VERSION 5.8 ;
BUSBITCHARS "[]" ;
DIVIDERCHAR "/" ;
UNITS
    DATABASE MICRONS 1000 ;
END UNITS

VIA ino_exec_arith_via1_2_1000_440_1_2_410_410
  VIARULE via1Array ;
  CUTSIZE 0.19 0.19 ;
  LAYERS Metal1 Via1 Metal2 ;
  CUTSPACING 0.22 0.22 ;
  ENCLOSURE 0.05 0.125 0.005 0.05 ;
  ROWCOL 1 2 ;
END ino_exec_arith_via1_2_1000_440_1_2_410_410

VIA ino_exec_arith_via2_3_1000_440_1_2_410_410
  VIARULE via2Array ;
  CUTSIZE 0.19 0.19 ;
  LAYERS Metal2 Via2 Metal3 ;
  CUTSPACING 0.22 0.22 ;
  ENCLOSURE 0.005 0.05 0.05 0.005 ;
  ROWCOL 1 2 ;
END ino_exec_arith_via2_3_1000_440_1_2_410_410

VIA ino_exec_arith_via3_4_1000_440_1_2_410_410
  VIARULE via3Array ;
  CUTSIZE 0.19 0.19 ;
  LAYERS Metal3 Via3 Metal4 ;
  CUTSPACING 0.22 0.22 ;
  ENCLOSURE 0.05 0.005 0.2 0.05 ;
  ROWCOL 1 2 ;
END ino_exec_arith_via3_4_1000_440_1_2_410_410

VIA ino_exec_arith_via4_5_1000_2000_1_1_840_840
  VIARULE viaTop1Array ;
  CUTSIZE 0.42 0.42 ;
  LAYERS Metal4 TopVia1 TopMetal1 ;
  CUTSPACING 0.42 0.42 ;
  ENCLOSURE 0.29 0.1 0.42 0.79 ;
END ino_exec_arith_via4_5_1000_2000_1_1_840_840

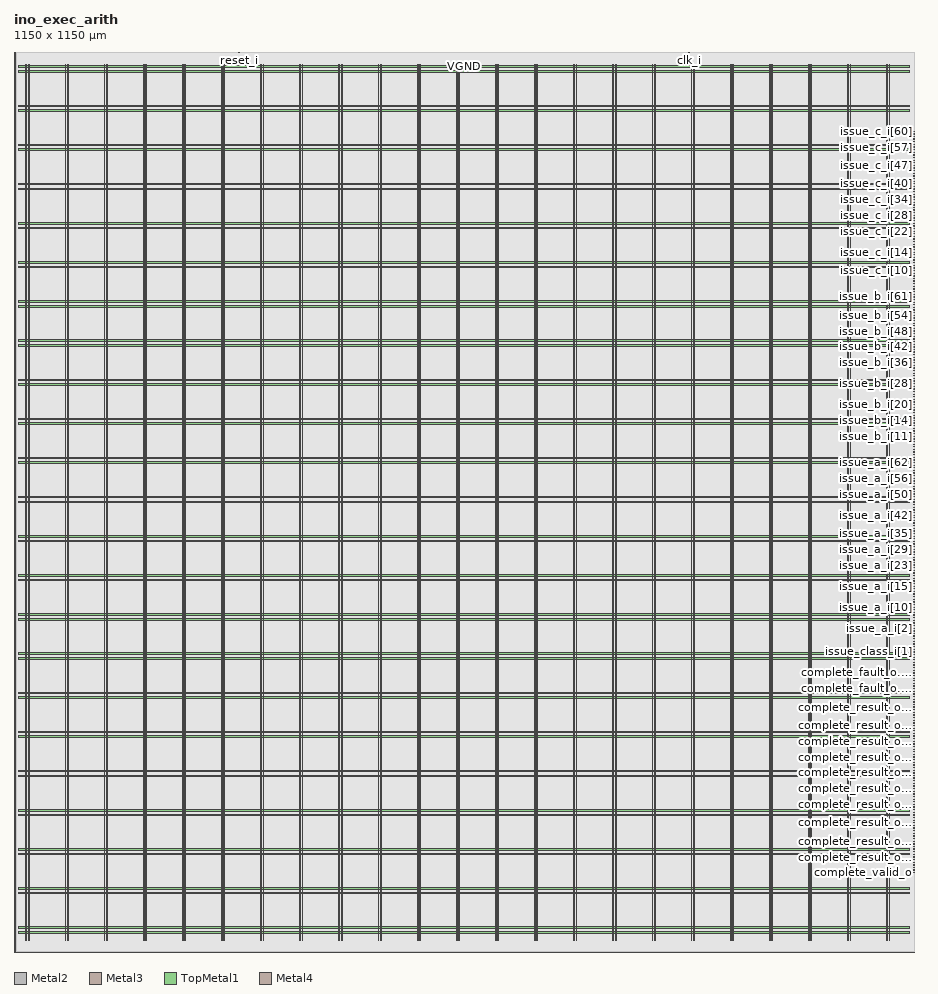
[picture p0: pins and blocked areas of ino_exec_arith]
MACRO ino_exec_arith
  FOREIGN ino_exec_arith 0 0 ;
  CLASS BLOCK ;
  SIZE 1150 BY 1150 ;
  PIN clk_i
    DIRECTION INPUT ;
    USE SIGNAL ;
    PORT
      LAYER Metal2 ;
        RECT  862.36 1149.6 862.76 1150 ;
    END
  END clk_i
  PIN complete_fault_o.code[0]
    DIRECTION OUTPUT ;
    USE SIGNAL ;
    PORT
      LAYER Metal3 ;
        RECT  1149.6 336.22 1150 336.62 ;
    END
  END complete_fault_o.code[0]
  PIN complete_fault_o.code[1]
    DIRECTION OUTPUT ;
    USE SIGNAL ;
    PORT
      LAYER Metal3 ;
        RECT  1149.6 339.58 1150 339.98 ;
    END
  END complete_fault_o.code[1]
  PIN complete_fault_o.code[2]
    DIRECTION OUTPUT ;
    USE SIGNAL ;
    PORT
      LAYER Metal3 ;
        RECT  1149.6 342.94 1150 343.34 ;
    END
  END complete_fault_o.code[2]
  PIN complete_fault_o.code[3]
    DIRECTION OUTPUT ;
    USE SIGNAL ;
    PORT
      LAYER Metal3 ;
        RECT  1149.6 346.3 1150 346.7 ;
    END
  END complete_fault_o.code[3]
  PIN complete_fault_o.code[4]
    DIRECTION OUTPUT ;
    USE SIGNAL ;
    PORT
      LAYER Metal3 ;
        RECT  1149.6 349.66 1150 350.06 ;
    END
  END complete_fault_o.code[4]
  PIN complete_fault_o.code[5]
    DIRECTION OUTPUT ;
    USE SIGNAL ;
    PORT
      LAYER Metal3 ;
        RECT  1149.6 353.02 1150 353.42 ;
    END
  END complete_fault_o.code[5]
  PIN complete_fault_o.code[6]
    DIRECTION OUTPUT ;
    USE SIGNAL ;
    PORT
      LAYER Metal3 ;
        RECT  1149.6 356.38 1150 356.78 ;
    END
  END complete_fault_o.code[6]
  PIN complete_fault_o.code[7]
    DIRECTION OUTPUT ;
    USE SIGNAL ;
    PORT
      LAYER Metal3 ;
        RECT  1149.6 359.74 1150 360.14 ;
    END
  END complete_fault_o.code[7]
  PIN complete_fault_o.valid
    DIRECTION OUTPUT ;
    USE SIGNAL ;
    PORT
      LAYER Metal3 ;
        RECT  1149.6 332.86 1150 333.26 ;
    END
  END complete_fault_o.valid
  PIN complete_result_o[0]
    DIRECTION OUTPUT ;
    USE SIGNAL ;
    PORT
      LAYER Metal3 ;
        RECT  1149.6 117.82 1150 118.22 ;
    END
  END complete_result_o[0]
  PIN complete_result_o[10]
    DIRECTION OUTPUT ;
    USE SIGNAL ;
    PORT
      LAYER Metal3 ;
        RECT  1149.6 151.42 1150 151.82 ;
    END
  END complete_result_o[10]
  PIN complete_result_o[11]
    DIRECTION OUTPUT ;
    USE SIGNAL ;
    PORT
      LAYER Metal3 ;
        RECT  1149.6 154.78 1150 155.18 ;
    END
  END complete_result_o[11]
  PIN complete_result_o[12]
    DIRECTION OUTPUT ;
    USE SIGNAL ;
    PORT
      LAYER Metal3 ;
        RECT  1149.6 158.14 1150 158.54 ;
    END
  END complete_result_o[12]
  PIN complete_result_o[13]
    DIRECTION OUTPUT ;
    USE SIGNAL ;
    PORT
      LAYER Metal3 ;
        RECT  1149.6 161.5 1150 161.9 ;
    END
  END complete_result_o[13]
  PIN complete_result_o[14]
    DIRECTION OUTPUT ;
    USE SIGNAL ;
    PORT
      LAYER Metal3 ;
        RECT  1149.6 164.86 1150 165.26 ;
    END
  END complete_result_o[14]
  PIN complete_result_o[15]
    DIRECTION OUTPUT ;
    USE SIGNAL ;
    PORT
      LAYER Metal3 ;
        RECT  1149.6 168.22 1150 168.62 ;
    END
  END complete_result_o[15]
  PIN complete_result_o[16]
    DIRECTION OUTPUT ;
    USE SIGNAL ;
    PORT
      LAYER Metal3 ;
        RECT  1149.6 171.58 1150 171.98 ;
    END
  END complete_result_o[16]
  PIN complete_result_o[17]
    DIRECTION OUTPUT ;
    USE SIGNAL ;
    PORT
      LAYER Metal3 ;
        RECT  1149.6 174.94 1150 175.34 ;
    END
  END complete_result_o[17]
  PIN complete_result_o[18]
    DIRECTION OUTPUT ;
    USE SIGNAL ;
    PORT
      LAYER Metal3 ;
        RECT  1149.6 178.3 1150 178.7 ;
    END
  END complete_result_o[18]
  PIN complete_result_o[19]
    DIRECTION OUTPUT ;
    USE SIGNAL ;
    PORT
      LAYER Metal3 ;
        RECT  1149.6 181.66 1150 182.06 ;
    END
  END complete_result_o[19]
  PIN complete_result_o[1]
    DIRECTION OUTPUT ;
    USE SIGNAL ;
    PORT
      LAYER Metal3 ;
        RECT  1149.6 121.18 1150 121.58 ;
    END
  END complete_result_o[1]
  PIN complete_result_o[20]
    DIRECTION OUTPUT ;
    USE SIGNAL ;
    PORT
      LAYER Metal3 ;
        RECT  1149.6 185.02 1150 185.42 ;
    END
  END complete_result_o[20]
  PIN complete_result_o[21]
    DIRECTION OUTPUT ;
    USE SIGNAL ;
    PORT
      LAYER Metal3 ;
        RECT  1149.6 188.38 1150 188.78 ;
    END
  END complete_result_o[21]
  PIN complete_result_o[22]
    DIRECTION OUTPUT ;
    USE SIGNAL ;
    PORT
      LAYER Metal3 ;
        RECT  1149.6 191.74 1150 192.14 ;
    END
  END complete_result_o[22]
  PIN complete_result_o[23]
    DIRECTION OUTPUT ;
    USE SIGNAL ;
    PORT
      LAYER Metal3 ;
        RECT  1149.6 195.1 1150 195.5 ;
    END
  END complete_result_o[23]
  PIN complete_result_o[24]
    DIRECTION OUTPUT ;
    USE SIGNAL ;
    PORT
      LAYER Metal3 ;
        RECT  1149.6 198.46 1150 198.86 ;
    END
  END complete_result_o[24]
  PIN complete_result_o[25]
    DIRECTION OUTPUT ;
    USE SIGNAL ;
    PORT
      LAYER Metal3 ;
        RECT  1149.6 201.82 1150 202.22 ;
    END
  END complete_result_o[25]
  PIN complete_result_o[26]
    DIRECTION OUTPUT ;
    USE SIGNAL ;
    PORT
      LAYER Metal3 ;
        RECT  1149.6 205.18 1150 205.58 ;
    END
  END complete_result_o[26]
  PIN complete_result_o[27]
    DIRECTION OUTPUT ;
    USE SIGNAL ;
    PORT
      LAYER Metal3 ;
        RECT  1149.6 208.54 1150 208.94 ;
    END
  END complete_result_o[27]
  PIN complete_result_o[28]
    DIRECTION OUTPUT ;
    USE SIGNAL ;
    PORT
      LAYER Metal3 ;
        RECT  1149.6 211.9 1150 212.3 ;
    END
  END complete_result_o[28]
  PIN complete_result_o[29]
    DIRECTION OUTPUT ;
    USE SIGNAL ;
    PORT
      LAYER Metal3 ;
        RECT  1149.6 215.26 1150 215.66 ;
    END
  END complete_result_o[29]
  PIN complete_result_o[2]
    DIRECTION OUTPUT ;
    USE SIGNAL ;
    PORT
      LAYER Metal3 ;
        RECT  1149.6 124.54 1150 124.94 ;
    END
  END complete_result_o[2]
  PIN complete_result_o[30]
    DIRECTION OUTPUT ;
    USE SIGNAL ;
    PORT
      LAYER Metal3 ;
        RECT  1149.6 218.62 1150 219.02 ;
    END
  END complete_result_o[30]
  PIN complete_result_o[31]
    DIRECTION OUTPUT ;
    USE SIGNAL ;
    PORT
      LAYER Metal3 ;
        RECT  1149.6 221.98 1150 222.38 ;
    END
  END complete_result_o[31]
  PIN complete_result_o[32]
    DIRECTION OUTPUT ;
    USE SIGNAL ;
    PORT
      LAYER Metal3 ;
        RECT  1149.6 225.34 1150 225.74 ;
    END
  END complete_result_o[32]
  PIN complete_result_o[33]
    DIRECTION OUTPUT ;
    USE SIGNAL ;
    PORT
      LAYER Metal3 ;
        RECT  1149.6 228.7 1150 229.1 ;
    END
  END complete_result_o[33]
  PIN complete_result_o[34]
    DIRECTION OUTPUT ;
    USE SIGNAL ;
    PORT
      LAYER Metal3 ;
        RECT  1149.6 232.06 1150 232.46 ;
    END
  END complete_result_o[34]
  PIN complete_result_o[35]
    DIRECTION OUTPUT ;
    USE SIGNAL ;
    PORT
      LAYER Metal3 ;
        RECT  1149.6 235.42 1150 235.82 ;
    END
  END complete_result_o[35]
  PIN complete_result_o[36]
    DIRECTION OUTPUT ;
    USE SIGNAL ;
    PORT
      LAYER Metal3 ;
        RECT  1149.6 238.78 1150 239.18 ;
    END
  END complete_result_o[36]
  PIN complete_result_o[37]
    DIRECTION OUTPUT ;
    USE SIGNAL ;
    PORT
      LAYER Metal3 ;
        RECT  1149.6 242.14 1150 242.54 ;
    END
  END complete_result_o[37]
  PIN complete_result_o[38]
    DIRECTION OUTPUT ;
    USE SIGNAL ;
    PORT
      LAYER Metal3 ;
        RECT  1149.6 245.5 1150 245.9 ;
    END
  END complete_result_o[38]
  PIN complete_result_o[39]
    DIRECTION OUTPUT ;
    USE SIGNAL ;
    PORT
      LAYER Metal3 ;
        RECT  1149.6 248.86 1150 249.26 ;
    END
  END complete_result_o[39]
  PIN complete_result_o[3]
    DIRECTION OUTPUT ;
    USE SIGNAL ;
    PORT
      LAYER Metal3 ;
        RECT  1149.6 127.9 1150 128.3 ;
    END
  END complete_result_o[3]
  PIN complete_result_o[40]
    DIRECTION OUTPUT ;
    USE SIGNAL ;
    PORT
      LAYER Metal3 ;
        RECT  1149.6 252.22 1150 252.62 ;
    END
  END complete_result_o[40]
  PIN complete_result_o[41]
    DIRECTION OUTPUT ;
    USE SIGNAL ;
    PORT
      LAYER Metal3 ;
        RECT  1149.6 255.58 1150 255.98 ;
    END
  END complete_result_o[41]
  PIN complete_result_o[42]
    DIRECTION OUTPUT ;
    USE SIGNAL ;
    PORT
      LAYER Metal3 ;
        RECT  1149.6 258.94 1150 259.34 ;
    END
  END complete_result_o[42]
  PIN complete_result_o[43]
    DIRECTION OUTPUT ;
    USE SIGNAL ;
    PORT
      LAYER Metal3 ;
        RECT  1149.6 262.3 1150 262.7 ;
    END
  END complete_result_o[43]
  PIN complete_result_o[44]
    DIRECTION OUTPUT ;
    USE SIGNAL ;
    PORT
      LAYER Metal3 ;
        RECT  1149.6 265.66 1150 266.06 ;
    END
  END complete_result_o[44]
  PIN complete_result_o[45]
    DIRECTION OUTPUT ;
    USE SIGNAL ;
    PORT
      LAYER Metal3 ;
        RECT  1149.6 269.02 1150 269.42 ;
    END
  END complete_result_o[45]
  PIN complete_result_o[46]
    DIRECTION OUTPUT ;
    USE SIGNAL ;
    PORT
      LAYER Metal3 ;
        RECT  1149.6 272.38 1150 272.78 ;
    END
  END complete_result_o[46]
  PIN complete_result_o[47]
    DIRECTION OUTPUT ;
    USE SIGNAL ;
    PORT
      LAYER Metal3 ;
        RECT  1149.6 275.74 1150 276.14 ;
    END
  END complete_result_o[47]
  PIN complete_result_o[48]
    DIRECTION OUTPUT ;
    USE SIGNAL ;
    PORT
      LAYER Metal3 ;
        RECT  1149.6 279.1 1150 279.5 ;
    END
  END complete_result_o[48]
  PIN complete_result_o[49]
    DIRECTION OUTPUT ;
    USE SIGNAL ;
    PORT
      LAYER Metal3 ;
        RECT  1149.6 282.46 1150 282.86 ;
    END
  END complete_result_o[49]
  PIN complete_result_o[4]
    DIRECTION OUTPUT ;
    USE SIGNAL ;
    PORT
      LAYER Metal3 ;
        RECT  1149.6 131.26 1150 131.66 ;
    END
  END complete_result_o[4]
  PIN complete_result_o[50]
    DIRECTION OUTPUT ;
    USE SIGNAL ;
    PORT
      LAYER Metal3 ;
        RECT  1149.6 285.82 1150 286.22 ;
    END
  END complete_result_o[50]
  PIN complete_result_o[51]
    DIRECTION OUTPUT ;
    USE SIGNAL ;
    PORT
      LAYER Metal3 ;
        RECT  1149.6 289.18 1150 289.58 ;
    END
  END complete_result_o[51]
  PIN complete_result_o[52]
    DIRECTION OUTPUT ;
    USE SIGNAL ;
    PORT
      LAYER Metal3 ;
        RECT  1149.6 292.54 1150 292.94 ;
    END
  END complete_result_o[52]
  PIN complete_result_o[53]
    DIRECTION OUTPUT ;
    USE SIGNAL ;
    PORT
      LAYER Metal3 ;
        RECT  1149.6 295.9 1150 296.3 ;
    END
  END complete_result_o[53]
  PIN complete_result_o[54]
    DIRECTION OUTPUT ;
    USE SIGNAL ;
    PORT
      LAYER Metal3 ;
        RECT  1149.6 299.26 1150 299.66 ;
    END
  END complete_result_o[54]
  PIN complete_result_o[55]
    DIRECTION OUTPUT ;
    USE SIGNAL ;
    PORT
      LAYER Metal3 ;
        RECT  1149.6 302.62 1150 303.02 ;
    END
  END complete_result_o[55]
  PIN complete_result_o[56]
    DIRECTION OUTPUT ;
    USE SIGNAL ;
    PORT
      LAYER Metal3 ;
        RECT  1149.6 305.98 1150 306.38 ;
    END
  END complete_result_o[56]
  PIN complete_result_o[57]
    DIRECTION OUTPUT ;
    USE SIGNAL ;
    PORT
      LAYER Metal3 ;
        RECT  1149.6 309.34 1150 309.74 ;
    END
  END complete_result_o[57]
  PIN complete_result_o[58]
    DIRECTION OUTPUT ;
    USE SIGNAL ;
    PORT
      LAYER Metal3 ;
        RECT  1149.6 312.7 1150 313.1 ;
    END
  END complete_result_o[58]
  PIN complete_result_o[59]
    DIRECTION OUTPUT ;
    USE SIGNAL ;
    PORT
      LAYER Metal3 ;
        RECT  1149.6 316.06 1150 316.46 ;
    END
  END complete_result_o[59]
  PIN complete_result_o[5]
    DIRECTION OUTPUT ;
    USE SIGNAL ;
    PORT
      LAYER Metal3 ;
        RECT  1149.6 134.62 1150 135.02 ;
    END
  END complete_result_o[5]
  PIN complete_result_o[60]
    DIRECTION OUTPUT ;
    USE SIGNAL ;
    PORT
      LAYER Metal3 ;
        RECT  1149.6 319.42 1150 319.82 ;
    END
  END complete_result_o[60]
  PIN complete_result_o[61]
    DIRECTION OUTPUT ;
    USE SIGNAL ;
    PORT
      LAYER Metal3 ;
        RECT  1149.6 322.78 1150 323.18 ;
    END
  END complete_result_o[61]
  PIN complete_result_o[62]
    DIRECTION OUTPUT ;
    USE SIGNAL ;
    PORT
      LAYER Metal3 ;
        RECT  1149.6 326.14 1150 326.54 ;
    END
  END complete_result_o[62]
  PIN complete_result_o[63]
    DIRECTION OUTPUT ;
    USE SIGNAL ;
    PORT
      LAYER Metal3 ;
        RECT  1149.6 329.5 1150 329.9 ;
    END
  END complete_result_o[63]
  PIN complete_result_o[6]
    DIRECTION OUTPUT ;
    USE SIGNAL ;
    PORT
      LAYER Metal3 ;
        RECT  1149.6 137.98 1150 138.38 ;
    END
  END complete_result_o[6]
  PIN complete_result_o[7]
    DIRECTION OUTPUT ;
    USE SIGNAL ;
    PORT
      LAYER Metal3 ;
        RECT  1149.6 141.34 1150 141.74 ;
    END
  END complete_result_o[7]
  PIN complete_result_o[8]
    DIRECTION OUTPUT ;
    USE SIGNAL ;
    PORT
      LAYER Metal3 ;
        RECT  1149.6 144.7 1150 145.1 ;
    END
  END complete_result_o[8]
  PIN complete_result_o[9]
    DIRECTION OUTPUT ;
    USE SIGNAL ;
    PORT
      LAYER Metal3 ;
        RECT  1149.6 148.06 1150 148.46 ;
    END
  END complete_result_o[9]
  PIN complete_result_valid_o
    DIRECTION OUTPUT ;
    USE SIGNAL ;
    PORT
      LAYER Metal3 ;
        RECT  1149.6 114.46 1150 114.86 ;
    END
  END complete_result_valid_o
  PIN complete_valid_o
    DIRECTION OUTPUT ;
    USE SIGNAL ;
    PORT
      LAYER Metal3 ;
        RECT  1149.6 111.1 1150 111.5 ;
    END
  END complete_valid_o
  PIN issue_a_i[0]
    DIRECTION INPUT ;
    USE SIGNAL ;
    PORT
      LAYER Metal3 ;
        RECT  1149.6 406.78 1150 407.18 ;
    END
  END issue_a_i[0]
  PIN issue_a_i[10]
    DIRECTION INPUT ;
    USE SIGNAL ;
    PORT
      LAYER Metal3 ;
        RECT  1149.6 440.38 1150 440.78 ;
    END
  END issue_a_i[10]
  PIN issue_a_i[11]
    DIRECTION INPUT ;
    USE SIGNAL ;
    PORT
      LAYER Metal3 ;
        RECT  1149.6 443.74 1150 444.14 ;
    END
  END issue_a_i[11]
  PIN issue_a_i[12]
    DIRECTION INPUT ;
    USE SIGNAL ;
    PORT
      LAYER Metal3 ;
        RECT  1149.6 447.1 1150 447.5 ;
    END
  END issue_a_i[12]
  PIN issue_a_i[13]
    DIRECTION INPUT ;
    USE SIGNAL ;
    PORT
      LAYER Metal3 ;
        RECT  1149.6 450.46 1150 450.86 ;
    END
  END issue_a_i[13]
  PIN issue_a_i[14]
    DIRECTION INPUT ;
    USE SIGNAL ;
    PORT
      LAYER Metal3 ;
        RECT  1149.6 453.82 1150 454.22 ;
    END
  END issue_a_i[14]
  PIN issue_a_i[15]
    DIRECTION INPUT ;
    USE SIGNAL ;
    PORT
      LAYER Metal3 ;
        RECT  1149.6 457.18 1150 457.58 ;
    END
  END issue_a_i[15]
  PIN issue_a_i[16]
    DIRECTION INPUT ;
    USE SIGNAL ;
    PORT
      LAYER Metal3 ;
        RECT  1149.6 460.54 1150 460.94 ;
    END
  END issue_a_i[16]
  PIN issue_a_i[17]
    DIRECTION INPUT ;
    USE SIGNAL ;
    PORT
      LAYER Metal3 ;
        RECT  1149.6 463.9 1150 464.3 ;
    END
  END issue_a_i[17]
  PIN issue_a_i[18]
    DIRECTION INPUT ;
    USE SIGNAL ;
    PORT
      LAYER Metal3 ;
        RECT  1149.6 467.26 1150 467.66 ;
    END
  END issue_a_i[18]
  PIN issue_a_i[19]
    DIRECTION INPUT ;
    USE SIGNAL ;
    PORT
      LAYER Metal3 ;
        RECT  1149.6 470.62 1150 471.02 ;
    END
  END issue_a_i[19]
  PIN issue_a_i[1]
    DIRECTION INPUT ;
    USE SIGNAL ;
    PORT
      LAYER Metal3 ;
        RECT  1149.6 410.14 1150 410.54 ;
    END
  END issue_a_i[1]
  PIN issue_a_i[20]
    DIRECTION INPUT ;
    USE SIGNAL ;
    PORT
      LAYER Metal3 ;
        RECT  1149.6 473.98 1150 474.38 ;
    END
  END issue_a_i[20]
  PIN issue_a_i[21]
    DIRECTION INPUT ;
    USE SIGNAL ;
    PORT
      LAYER Metal3 ;
        RECT  1149.6 477.34 1150 477.74 ;
    END
  END issue_a_i[21]
  PIN issue_a_i[22]
    DIRECTION INPUT ;
    USE SIGNAL ;
    PORT
      LAYER Metal3 ;
        RECT  1149.6 480.7 1150 481.1 ;
    END
  END issue_a_i[22]
  PIN issue_a_i[23]
    DIRECTION INPUT ;
    USE SIGNAL ;
    PORT
      LAYER Metal3 ;
        RECT  1149.6 484.06 1150 484.46 ;
    END
  END issue_a_i[23]
  PIN issue_a_i[24]
    DIRECTION INPUT ;
    USE SIGNAL ;
    PORT
      LAYER Metal3 ;
        RECT  1149.6 487.42 1150 487.82 ;
    END
  END issue_a_i[24]
  PIN issue_a_i[25]
    DIRECTION INPUT ;
    USE SIGNAL ;
    PORT
      LAYER Metal3 ;
        RECT  1149.6 490.78 1150 491.18 ;
    END
  END issue_a_i[25]
  PIN issue_a_i[26]
    DIRECTION INPUT ;
    USE SIGNAL ;
    PORT
      LAYER Metal3 ;
        RECT  1149.6 494.14 1150 494.54 ;
    END
  END issue_a_i[26]
  PIN issue_a_i[27]
    DIRECTION INPUT ;
    USE SIGNAL ;
    PORT
      LAYER Metal3 ;
        RECT  1149.6 497.5 1150 497.9 ;
    END
  END issue_a_i[27]
  PIN issue_a_i[28]
    DIRECTION INPUT ;
    USE SIGNAL ;
    PORT
      LAYER Metal3 ;
        RECT  1149.6 500.86 1150 501.26 ;
    END
  END issue_a_i[28]
  PIN issue_a_i[29]
    DIRECTION INPUT ;
    USE SIGNAL ;
    PORT
      LAYER Metal3 ;
        RECT  1149.6 504.22 1150 504.62 ;
    END
  END issue_a_i[29]
  PIN issue_a_i[2]
    DIRECTION INPUT ;
    USE SIGNAL ;
    PORT
      LAYER Metal3 ;
        RECT  1149.6 413.5 1150 413.9 ;
    END
  END issue_a_i[2]
  PIN issue_a_i[30]
    DIRECTION INPUT ;
    USE SIGNAL ;
    PORT
      LAYER Metal3 ;
        RECT  1149.6 507.58 1150 507.98 ;
    END
  END issue_a_i[30]
  PIN issue_a_i[31]
    DIRECTION INPUT ;
    USE SIGNAL ;
    PORT
      LAYER Metal3 ;
        RECT  1149.6 510.94 1150 511.34 ;
    END
  END issue_a_i[31]
  PIN issue_a_i[32]
    DIRECTION INPUT ;
    USE SIGNAL ;
    PORT
      LAYER Metal3 ;
        RECT  1149.6 514.3 1150 514.7 ;
    END
  END issue_a_i[32]
  PIN issue_a_i[33]
    DIRECTION INPUT ;
    USE SIGNAL ;
    PORT
      LAYER Metal3 ;
        RECT  1149.6 517.66 1150 518.06 ;
    END
  END issue_a_i[33]
  PIN issue_a_i[34]
    DIRECTION INPUT ;
    USE SIGNAL ;
    PORT
      LAYER Metal3 ;
        RECT  1149.6 521.02 1150 521.42 ;
    END
  END issue_a_i[34]
  PIN issue_a_i[35]
    DIRECTION INPUT ;
    USE SIGNAL ;
    PORT
      LAYER Metal3 ;
        RECT  1149.6 524.38 1150 524.78 ;
    END
  END issue_a_i[35]
  PIN issue_a_i[36]
    DIRECTION INPUT ;
    USE SIGNAL ;
    PORT
      LAYER Metal3 ;
        RECT  1149.6 527.74 1150 528.14 ;
    END
  END issue_a_i[36]
  PIN issue_a_i[37]
    DIRECTION INPUT ;
    USE SIGNAL ;
    PORT
      LAYER Metal3 ;
        RECT  1149.6 531.1 1150 531.5 ;
    END
  END issue_a_i[37]
  PIN issue_a_i[38]
    DIRECTION INPUT ;
    USE SIGNAL ;
    PORT
      LAYER Metal3 ;
        RECT  1149.6 534.46 1150 534.86 ;
    END
  END issue_a_i[38]
  PIN issue_a_i[39]
    DIRECTION INPUT ;
    USE SIGNAL ;
    PORT
      LAYER Metal3 ;
        RECT  1149.6 537.82 1150 538.22 ;
    END
  END issue_a_i[39]
  PIN issue_a_i[3]
    DIRECTION INPUT ;
    USE SIGNAL ;
    PORT
      LAYER Metal3 ;
        RECT  1149.6 416.86 1150 417.26 ;
    END
  END issue_a_i[3]
  PIN issue_a_i[40]
    DIRECTION INPUT ;
    USE SIGNAL ;
    PORT
      LAYER Metal3 ;
        RECT  1149.6 541.18 1150 541.58 ;
    END
  END issue_a_i[40]
  PIN issue_a_i[41]
    DIRECTION INPUT ;
    USE SIGNAL ;
    PORT
      LAYER Metal3 ;
        RECT  1149.6 544.54 1150 544.94 ;
    END
  END issue_a_i[41]
  PIN issue_a_i[42]
    DIRECTION INPUT ;
    USE SIGNAL ;
    PORT
      LAYER Metal3 ;
        RECT  1149.6 547.9 1150 548.3 ;
    END
  END issue_a_i[42]
  PIN issue_a_i[43]
    DIRECTION INPUT ;
    USE SIGNAL ;
    PORT
      LAYER Metal3 ;
        RECT  1149.6 551.26 1150 551.66 ;
    END
  END issue_a_i[43]
  PIN issue_a_i[44]
    DIRECTION INPUT ;
    USE SIGNAL ;
    PORT
      LAYER Metal3 ;
        RECT  1149.6 554.62 1150 555.02 ;
    END
  END issue_a_i[44]
  PIN issue_a_i[45]
    DIRECTION INPUT ;
    USE SIGNAL ;
    PORT
      LAYER Metal3 ;
        RECT  1149.6 557.98 1150 558.38 ;
    END
  END issue_a_i[45]
  PIN issue_a_i[46]
    DIRECTION INPUT ;
    USE SIGNAL ;
    PORT
      LAYER Metal3 ;
        RECT  1149.6 561.34 1150 561.74 ;
    END
  END issue_a_i[46]
  PIN issue_a_i[47]
    DIRECTION INPUT ;
    USE SIGNAL ;
    PORT
      LAYER Metal3 ;
        RECT  1149.6 564.7 1150 565.1 ;
    END
  END issue_a_i[47]
  PIN issue_a_i[48]
    DIRECTION INPUT ;
    USE SIGNAL ;
    PORT
      LAYER Metal3 ;
        RECT  1149.6 568.06 1150 568.46 ;
    END
  END issue_a_i[48]
  PIN issue_a_i[49]
    DIRECTION INPUT ;
    USE SIGNAL ;
    PORT
      LAYER Metal3 ;
        RECT  1149.6 571.42 1150 571.82 ;
    END
  END issue_a_i[49]
  PIN issue_a_i[4]
    DIRECTION INPUT ;
    USE SIGNAL ;
    PORT
      LAYER Metal3 ;
        RECT  1149.6 420.22 1150 420.62 ;
    END
  END issue_a_i[4]
  PIN issue_a_i[50]
    DIRECTION INPUT ;
    USE SIGNAL ;
    PORT
      LAYER Metal3 ;
        RECT  1149.6 574.78 1150 575.18 ;
    END
  END issue_a_i[50]
  PIN issue_a_i[51]
    DIRECTION INPUT ;
    USE SIGNAL ;
    PORT
      LAYER Metal3 ;
        RECT  1149.6 578.14 1150 578.54 ;
    END
  END issue_a_i[51]
  PIN issue_a_i[52]
    DIRECTION INPUT ;
    USE SIGNAL ;
    PORT
      LAYER Metal3 ;
        RECT  1149.6 581.5 1150 581.9 ;
    END
  END issue_a_i[52]
  PIN issue_a_i[53]
    DIRECTION INPUT ;
    USE SIGNAL ;
    PORT
      LAYER Metal3 ;
        RECT  1149.6 584.86 1150 585.26 ;
    END
  END issue_a_i[53]
  PIN issue_a_i[54]
    DIRECTION INPUT ;
    USE SIGNAL ;
    PORT
      LAYER Metal3 ;
        RECT  1149.6 588.22 1150 588.62 ;
    END
  END issue_a_i[54]
  PIN issue_a_i[55]
    DIRECTION INPUT ;
    USE SIGNAL ;
    PORT
      LAYER Metal3 ;
        RECT  1149.6 591.58 1150 591.98 ;
    END
  END issue_a_i[55]
  PIN issue_a_i[56]
    DIRECTION INPUT ;
    USE SIGNAL ;
    PORT
      LAYER Metal3 ;
        RECT  1149.6 594.94 1150 595.34 ;
    END
  END issue_a_i[56]
  PIN issue_a_i[57]
    DIRECTION INPUT ;
    USE SIGNAL ;
    PORT
      LAYER Metal3 ;
        RECT  1149.6 598.3 1150 598.7 ;
    END
  END issue_a_i[57]
  PIN issue_a_i[58]
    DIRECTION INPUT ;
    USE SIGNAL ;
    PORT
      LAYER Metal3 ;
        RECT  1149.6 601.66 1150 602.06 ;
    END
  END issue_a_i[58]
  PIN issue_a_i[59]
    DIRECTION INPUT ;
    USE SIGNAL ;
    PORT
      LAYER Metal3 ;
        RECT  1149.6 605.02 1150 605.42 ;
    END
  END issue_a_i[59]
  PIN issue_a_i[5]
    DIRECTION INPUT ;
    USE SIGNAL ;
    PORT
      LAYER Metal3 ;
        RECT  1149.6 423.58 1150 423.98 ;
    END
  END issue_a_i[5]
  PIN issue_a_i[60]
    DIRECTION INPUT ;
    USE SIGNAL ;
    PORT
      LAYER Metal3 ;
        RECT  1149.6 608.38 1150 608.78 ;
    END
  END issue_a_i[60]
  PIN issue_a_i[61]
    DIRECTION INPUT ;
    USE SIGNAL ;
    PORT
      LAYER Metal3 ;
        RECT  1149.6 611.74 1150 612.14 ;
    END
  END issue_a_i[61]
  PIN issue_a_i[62]
    DIRECTION INPUT ;
    USE SIGNAL ;
    PORT
      LAYER Metal3 ;
        RECT  1149.6 615.1 1150 615.5 ;
    END
  END issue_a_i[62]
  PIN issue_a_i[63]
    DIRECTION INPUT ;
    USE SIGNAL ;
    PORT
      LAYER Metal3 ;
        RECT  1149.6 618.46 1150 618.86 ;
    END
  END issue_a_i[63]
  PIN issue_a_i[6]
    DIRECTION INPUT ;
    USE SIGNAL ;
    PORT
      LAYER Metal3 ;
        RECT  1149.6 426.94 1150 427.34 ;
    END
  END issue_a_i[6]
  PIN issue_a_i[7]
    DIRECTION INPUT ;
    USE SIGNAL ;
    PORT
      LAYER Metal3 ;
        RECT  1149.6 430.3 1150 430.7 ;
    END
  END issue_a_i[7]
  PIN issue_a_i[8]
    DIRECTION INPUT ;
    USE SIGNAL ;
    PORT
      LAYER Metal3 ;
        RECT  1149.6 433.66 1150 434.06 ;
    END
  END issue_a_i[8]
  PIN issue_a_i[9]
    DIRECTION INPUT ;
    USE SIGNAL ;
    PORT
      LAYER Metal3 ;
        RECT  1149.6 437.02 1150 437.42 ;
    END
  END issue_a_i[9]
  PIN issue_b_i[0]
    DIRECTION INPUT ;
    USE SIGNAL ;
    PORT
      LAYER Metal3 ;
        RECT  1149.6 621.82 1150 622.22 ;
    END
  END issue_b_i[0]
  PIN issue_b_i[10]
    DIRECTION INPUT ;
    USE SIGNAL ;
    PORT
      LAYER Metal3 ;
        RECT  1149.6 655.42 1150 655.82 ;
    END
  END issue_b_i[10]
  PIN issue_b_i[11]
    DIRECTION INPUT ;
    USE SIGNAL ;
    PORT
      LAYER Metal3 ;
        RECT  1149.6 658.78 1150 659.18 ;
    END
  END issue_b_i[11]
  PIN issue_b_i[12]
    DIRECTION INPUT ;
    USE SIGNAL ;
    PORT
      LAYER Metal3 ;
        RECT  1149.6 662.14 1150 662.54 ;
    END
  END issue_b_i[12]
  PIN issue_b_i[13]
    DIRECTION INPUT ;
    USE SIGNAL ;
    PORT
      LAYER Metal3 ;
        RECT  1149.6 665.5 1150 665.9 ;
    END
  END issue_b_i[13]
  PIN issue_b_i[14]
    DIRECTION INPUT ;
    USE SIGNAL ;
    PORT
      LAYER Metal3 ;
        RECT  1149.6 668.86 1150 669.26 ;
    END
  END issue_b_i[14]
  PIN issue_b_i[15]
    DIRECTION INPUT ;
    USE SIGNAL ;
    PORT
      LAYER Metal3 ;
        RECT  1149.6 672.22 1150 672.62 ;
    END
  END issue_b_i[15]
  PIN issue_b_i[16]
    DIRECTION INPUT ;
    USE SIGNAL ;
    PORT
      LAYER Metal3 ;
        RECT  1149.6 675.58 1150 675.98 ;
    END
  END issue_b_i[16]
  PIN issue_b_i[17]
    DIRECTION INPUT ;
    USE SIGNAL ;
    PORT
      LAYER Metal3 ;
        RECT  1149.6 678.94 1150 679.34 ;
    END
  END issue_b_i[17]
  PIN issue_b_i[18]
    DIRECTION INPUT ;
    USE SIGNAL ;
    PORT
      LAYER Metal3 ;
        RECT  1149.6 682.3 1150 682.7 ;
    END
  END issue_b_i[18]
  PIN issue_b_i[19]
    DIRECTION INPUT ;
    USE SIGNAL ;
    PORT
      LAYER Metal3 ;
        RECT  1149.6 685.66 1150 686.06 ;
    END
  END issue_b_i[19]
  PIN issue_b_i[1]
    DIRECTION INPUT ;
    USE SIGNAL ;
    PORT
      LAYER Metal3 ;
        RECT  1149.6 625.18 1150 625.58 ;
    END
  END issue_b_i[1]
  PIN issue_b_i[20]
    DIRECTION INPUT ;
    USE SIGNAL ;
    PORT
      LAYER Metal3 ;
        RECT  1149.6 689.02 1150 689.42 ;
    END
  END issue_b_i[20]
  PIN issue_b_i[21]
    DIRECTION INPUT ;
    USE SIGNAL ;
    PORT
      LAYER Metal3 ;
        RECT  1149.6 692.38 1150 692.78 ;
    END
  END issue_b_i[21]
  PIN issue_b_i[22]
    DIRECTION INPUT ;
    USE SIGNAL ;
    PORT
      LAYER Metal3 ;
        RECT  1149.6 695.74 1150 696.14 ;
    END
  END issue_b_i[22]
  PIN issue_b_i[23]
    DIRECTION INPUT ;
    USE SIGNAL ;
    PORT
      LAYER Metal3 ;
        RECT  1149.6 699.1 1150 699.5 ;
    END
  END issue_b_i[23]
  PIN issue_b_i[24]
    DIRECTION INPUT ;
    USE SIGNAL ;
    PORT
      LAYER Metal3 ;
        RECT  1149.6 702.46 1150 702.86 ;
    END
  END issue_b_i[24]
  PIN issue_b_i[25]
    DIRECTION INPUT ;
    USE SIGNAL ;
    PORT
      LAYER Metal3 ;
        RECT  1149.6 705.82 1150 706.22 ;
    END
  END issue_b_i[25]
  PIN issue_b_i[26]
    DIRECTION INPUT ;
    USE SIGNAL ;
    PORT
      LAYER Metal3 ;
        RECT  1149.6 709.18 1150 709.58 ;
    END
  END issue_b_i[26]
  PIN issue_b_i[27]
    DIRECTION INPUT ;
    USE SIGNAL ;
    PORT
      LAYER Metal3 ;
        RECT  1149.6 712.54 1150 712.94 ;
    END
  END issue_b_i[27]
  PIN issue_b_i[28]
    DIRECTION INPUT ;
    USE SIGNAL ;
    PORT
      LAYER Metal3 ;
        RECT  1149.6 715.9 1150 716.3 ;
    END
  END issue_b_i[28]
  PIN issue_b_i[29]
    DIRECTION INPUT ;
    USE SIGNAL ;
    PORT
      LAYER Metal3 ;
        RECT  1149.6 719.26 1150 719.66 ;
    END
  END issue_b_i[29]
  PIN issue_b_i[2]
    DIRECTION INPUT ;
    USE SIGNAL ;
    PORT
      LAYER Metal3 ;
        RECT  1149.6 628.54 1150 628.94 ;
    END
  END issue_b_i[2]
  PIN issue_b_i[30]
    DIRECTION INPUT ;
    USE SIGNAL ;
    PORT
      LAYER Metal3 ;
        RECT  1149.6 722.62 1150 723.02 ;
    END
  END issue_b_i[30]
  PIN issue_b_i[31]
    DIRECTION INPUT ;
    USE SIGNAL ;
    PORT
      LAYER Metal3 ;
        RECT  1149.6 725.98 1150 726.38 ;
    END
  END issue_b_i[31]
  PIN issue_b_i[32]
    DIRECTION INPUT ;
    USE SIGNAL ;
    PORT
      LAYER Metal3 ;
        RECT  1149.6 729.34 1150 729.74 ;
    END
  END issue_b_i[32]
  PIN issue_b_i[33]
    DIRECTION INPUT ;
    USE SIGNAL ;
    PORT
      LAYER Metal3 ;
        RECT  1149.6 732.7 1150 733.1 ;
    END
  END issue_b_i[33]
  PIN issue_b_i[34]
    DIRECTION INPUT ;
    USE SIGNAL ;
    PORT
      LAYER Metal3 ;
        RECT  1149.6 736.06 1150 736.46 ;
    END
  END issue_b_i[34]
  PIN issue_b_i[35]
    DIRECTION INPUT ;
    USE SIGNAL ;
    PORT
      LAYER Metal3 ;
        RECT  1149.6 739.42 1150 739.82 ;
    END
  END issue_b_i[35]
  PIN issue_b_i[36]
    DIRECTION INPUT ;
    USE SIGNAL ;
    PORT
      LAYER Metal3 ;
        RECT  1149.6 742.78 1150 743.18 ;
    END
  END issue_b_i[36]
  PIN issue_b_i[37]
    DIRECTION INPUT ;
    USE SIGNAL ;
    PORT
      LAYER Metal3 ;
        RECT  1149.6 746.14 1150 746.54 ;
    END
  END issue_b_i[37]
  PIN issue_b_i[38]
    DIRECTION INPUT ;
    USE SIGNAL ;
    PORT
      LAYER Metal3 ;
        RECT  1149.6 749.5 1150 749.9 ;
    END
  END issue_b_i[38]
  PIN issue_b_i[39]
    DIRECTION INPUT ;
    USE SIGNAL ;
    PORT
      LAYER Metal3 ;
        RECT  1149.6 752.86 1150 753.26 ;
    END
  END issue_b_i[39]
  PIN issue_b_i[3]
    DIRECTION INPUT ;
    USE SIGNAL ;
    PORT
      LAYER Metal3 ;
        RECT  1149.6 631.9 1150 632.3 ;
    END
  END issue_b_i[3]
  PIN issue_b_i[40]
    DIRECTION INPUT ;
    USE SIGNAL ;
    PORT
      LAYER Metal3 ;
        RECT  1149.6 756.22 1150 756.62 ;
    END
  END issue_b_i[40]
  PIN issue_b_i[41]
    DIRECTION INPUT ;
    USE SIGNAL ;
    PORT
      LAYER Metal3 ;
        RECT  1149.6 759.58 1150 759.98 ;
    END
  END issue_b_i[41]
  PIN issue_b_i[42]
    DIRECTION INPUT ;
    USE SIGNAL ;
    PORT
      LAYER Metal3 ;
        RECT  1149.6 762.94 1150 763.34 ;
    END
  END issue_b_i[42]
  PIN issue_b_i[43]
    DIRECTION INPUT ;
    USE SIGNAL ;
    PORT
      LAYER Metal3 ;
        RECT  1149.6 766.3 1150 766.7 ;
    END
  END issue_b_i[43]
  PIN issue_b_i[44]
    DIRECTION INPUT ;
    USE SIGNAL ;
    PORT
      LAYER Metal3 ;
        RECT  1149.6 769.66 1150 770.06 ;
    END
  END issue_b_i[44]
  PIN issue_b_i[45]
    DIRECTION INPUT ;
    USE SIGNAL ;
    PORT
      LAYER Metal3 ;
        RECT  1149.6 773.02 1150 773.42 ;
    END
  END issue_b_i[45]
  PIN issue_b_i[46]
    DIRECTION INPUT ;
    USE SIGNAL ;
    PORT
      LAYER Metal3 ;
        RECT  1149.6 776.38 1150 776.78 ;
    END
  END issue_b_i[46]
  PIN issue_b_i[47]
    DIRECTION INPUT ;
    USE SIGNAL ;
    PORT
      LAYER Metal3 ;
        RECT  1149.6 779.74 1150 780.14 ;
    END
  END issue_b_i[47]
  PIN issue_b_i[48]
    DIRECTION INPUT ;
    USE SIGNAL ;
    PORT
      LAYER Metal3 ;
        RECT  1149.6 783.1 1150 783.5 ;
    END
  END issue_b_i[48]
  PIN issue_b_i[49]
    DIRECTION INPUT ;
    USE SIGNAL ;
    PORT
      LAYER Metal3 ;
        RECT  1149.6 786.46 1150 786.86 ;
    END
  END issue_b_i[49]
  PIN issue_b_i[4]
    DIRECTION INPUT ;
    USE SIGNAL ;
    PORT
      LAYER Metal3 ;
        RECT  1149.6 635.26 1150 635.66 ;
    END
  END issue_b_i[4]
  PIN issue_b_i[50]
    DIRECTION INPUT ;
    USE SIGNAL ;
    PORT
      LAYER Metal3 ;
        RECT  1149.6 789.82 1150 790.22 ;
    END
  END issue_b_i[50]
  PIN issue_b_i[51]
    DIRECTION INPUT ;
    USE SIGNAL ;
    PORT
      LAYER Metal3 ;
        RECT  1149.6 793.18 1150 793.58 ;
    END
  END issue_b_i[51]
  PIN issue_b_i[52]
    DIRECTION INPUT ;
    USE SIGNAL ;
    PORT
      LAYER Metal3 ;
        RECT  1149.6 796.54 1150 796.94 ;
    END
  END issue_b_i[52]
  PIN issue_b_i[53]
    DIRECTION INPUT ;
    USE SIGNAL ;
    PORT
      LAYER Metal3 ;
        RECT  1149.6 799.9 1150 800.3 ;
    END
  END issue_b_i[53]
  PIN issue_b_i[54]
    DIRECTION INPUT ;
    USE SIGNAL ;
    PORT
      LAYER Metal3 ;
        RECT  1149.6 803.26 1150 803.66 ;
    END
  END issue_b_i[54]
  PIN issue_b_i[55]
    DIRECTION INPUT ;
    USE SIGNAL ;
    PORT
      LAYER Metal3 ;
        RECT  1149.6 806.62 1150 807.02 ;
    END
  END issue_b_i[55]
  PIN issue_b_i[56]
    DIRECTION INPUT ;
    USE SIGNAL ;
    PORT
      LAYER Metal3 ;
        RECT  1149.6 809.98 1150 810.38 ;
    END
  END issue_b_i[56]
  PIN issue_b_i[57]
    DIRECTION INPUT ;
    USE SIGNAL ;
    PORT
      LAYER Metal3 ;
        RECT  1149.6 813.34 1150 813.74 ;
    END
  END issue_b_i[57]
  PIN issue_b_i[58]
    DIRECTION INPUT ;
    USE SIGNAL ;
    PORT
      LAYER Metal3 ;
        RECT  1149.6 816.7 1150 817.1 ;
    END
  END issue_b_i[58]
  PIN issue_b_i[59]
    DIRECTION INPUT ;
    USE SIGNAL ;
    PORT
      LAYER Metal3 ;
        RECT  1149.6 820.06 1150 820.46 ;
    END
  END issue_b_i[59]
  PIN issue_b_i[5]
    DIRECTION INPUT ;
    USE SIGNAL ;
    PORT
      LAYER Metal3 ;
        RECT  1149.6 638.62 1150 639.02 ;
    END
  END issue_b_i[5]
  PIN issue_b_i[60]
    DIRECTION INPUT ;
    USE SIGNAL ;
    PORT
      LAYER Metal3 ;
        RECT  1149.6 823.42 1150 823.82 ;
    END
  END issue_b_i[60]
  PIN issue_b_i[61]
    DIRECTION INPUT ;
    USE SIGNAL ;
    PORT
      LAYER Metal3 ;
        RECT  1149.6 826.78 1150 827.18 ;
    END
  END issue_b_i[61]
  PIN issue_b_i[62]
    DIRECTION INPUT ;
    USE SIGNAL ;
    PORT
      LAYER Metal3 ;
        RECT  1149.6 830.14 1150 830.54 ;
    END
  END issue_b_i[62]
  PIN issue_b_i[63]
    DIRECTION INPUT ;
    USE SIGNAL ;
    PORT
      LAYER Metal3 ;
        RECT  1149.6 833.5 1150 833.9 ;
    END
  END issue_b_i[63]
  PIN issue_b_i[6]
    DIRECTION INPUT ;
    USE SIGNAL ;
    PORT
      LAYER Metal3 ;
        RECT  1149.6 641.98 1150 642.38 ;
    END
  END issue_b_i[6]
  PIN issue_b_i[7]
    DIRECTION INPUT ;
    USE SIGNAL ;
    PORT
      LAYER Metal3 ;
        RECT  1149.6 645.34 1150 645.74 ;
    END
  END issue_b_i[7]
  PIN issue_b_i[8]
    DIRECTION INPUT ;
    USE SIGNAL ;
    PORT
      LAYER Metal3 ;
        RECT  1149.6 648.7 1150 649.1 ;
    END
  END issue_b_i[8]
  PIN issue_b_i[9]
    DIRECTION INPUT ;
    USE SIGNAL ;
    PORT
      LAYER Metal3 ;
        RECT  1149.6 652.06 1150 652.46 ;
    END
  END issue_b_i[9]
  PIN issue_c_i[0]
    DIRECTION INPUT ;
    USE SIGNAL ;
    PORT
      LAYER Metal3 ;
        RECT  1149.6 836.86 1150 837.26 ;
    END
  END issue_c_i[0]
  PIN issue_c_i[10]
    DIRECTION INPUT ;
    USE SIGNAL ;
    PORT
      LAYER Metal3 ;
        RECT  1149.6 870.46 1150 870.86 ;
    END
  END issue_c_i[10]
  PIN issue_c_i[11]
    DIRECTION INPUT ;
    USE SIGNAL ;
    PORT
      LAYER Metal3 ;
        RECT  1149.6 873.82 1150 874.22 ;
    END
  END issue_c_i[11]
  PIN issue_c_i[12]
    DIRECTION INPUT ;
    USE SIGNAL ;
    PORT
      LAYER Metal3 ;
        RECT  1149.6 877.18 1150 877.58 ;
    END
  END issue_c_i[12]
  PIN issue_c_i[13]
    DIRECTION INPUT ;
    USE SIGNAL ;
    PORT
      LAYER Metal3 ;
        RECT  1149.6 880.54 1150 880.94 ;
    END
  END issue_c_i[13]
  PIN issue_c_i[14]
    DIRECTION INPUT ;
    USE SIGNAL ;
    PORT
      LAYER Metal3 ;
        RECT  1149.6 883.9 1150 884.3 ;
    END
  END issue_c_i[14]
  PIN issue_c_i[15]
    DIRECTION INPUT ;
    USE SIGNAL ;
    PORT
      LAYER Metal3 ;
        RECT  1149.6 887.26 1150 887.66 ;
    END
  END issue_c_i[15]
  PIN issue_c_i[16]
    DIRECTION INPUT ;
    USE SIGNAL ;
    PORT
      LAYER Metal3 ;
        RECT  1149.6 890.62 1150 891.02 ;
    END
  END issue_c_i[16]
  PIN issue_c_i[17]
    DIRECTION INPUT ;
    USE SIGNAL ;
    PORT
      LAYER Metal3 ;
        RECT  1149.6 893.98 1150 894.38 ;
    END
  END issue_c_i[17]
  PIN issue_c_i[18]
    DIRECTION INPUT ;
    USE SIGNAL ;
    PORT
      LAYER Metal3 ;
        RECT  1149.6 897.34 1150 897.74 ;
    END
  END issue_c_i[18]
  PIN issue_c_i[19]
    DIRECTION INPUT ;
    USE SIGNAL ;
    PORT
      LAYER Metal3 ;
        RECT  1149.6 900.7 1150 901.1 ;
    END
  END issue_c_i[19]
  PIN issue_c_i[1]
    DIRECTION INPUT ;
    USE SIGNAL ;
    PORT
      LAYER Metal3 ;
        RECT  1149.6 840.22 1150 840.62 ;
    END
  END issue_c_i[1]
  PIN issue_c_i[20]
    DIRECTION INPUT ;
    USE SIGNAL ;
    PORT
      LAYER Metal3 ;
        RECT  1149.6 904.06 1150 904.46 ;
    END
  END issue_c_i[20]
  PIN issue_c_i[21]
    DIRECTION INPUT ;
    USE SIGNAL ;
    PORT
      LAYER Metal3 ;
        RECT  1149.6 907.42 1150 907.82 ;
    END
  END issue_c_i[21]
  PIN issue_c_i[22]
    DIRECTION INPUT ;
    USE SIGNAL ;
    PORT
      LAYER Metal3 ;
        RECT  1149.6 910.78 1150 911.18 ;
    END
  END issue_c_i[22]
  PIN issue_c_i[23]
    DIRECTION INPUT ;
    USE SIGNAL ;
    PORT
      LAYER Metal3 ;
        RECT  1149.6 914.14 1150 914.54 ;
    END
  END issue_c_i[23]
  PIN issue_c_i[24]
    DIRECTION INPUT ;
    USE SIGNAL ;
    PORT
      LAYER Metal3 ;
        RECT  1149.6 917.5 1150 917.9 ;
    END
  END issue_c_i[24]
  PIN issue_c_i[25]
    DIRECTION INPUT ;
    USE SIGNAL ;
    PORT
      LAYER Metal3 ;
        RECT  1149.6 920.86 1150 921.26 ;
    END
  END issue_c_i[25]
  PIN issue_c_i[26]
    DIRECTION INPUT ;
    USE SIGNAL ;
    PORT
      LAYER Metal3 ;
        RECT  1149.6 924.22 1150 924.62 ;
    END
  END issue_c_i[26]
  PIN issue_c_i[27]
    DIRECTION INPUT ;
    USE SIGNAL ;
    PORT
      LAYER Metal3 ;
        RECT  1149.6 927.58 1150 927.98 ;
    END
  END issue_c_i[27]
  PIN issue_c_i[28]
    DIRECTION INPUT ;
    USE SIGNAL ;
    PORT
      LAYER Metal3 ;
        RECT  1149.6 930.94 1150 931.34 ;
    END
  END issue_c_i[28]
  PIN issue_c_i[29]
    DIRECTION INPUT ;
    USE SIGNAL ;
    PORT
      LAYER Metal3 ;
        RECT  1149.6 934.3 1150 934.7 ;
    END
  END issue_c_i[29]
  PIN issue_c_i[2]
    DIRECTION INPUT ;
    USE SIGNAL ;
    PORT
      LAYER Metal3 ;
        RECT  1149.6 843.58 1150 843.98 ;
    END
  END issue_c_i[2]
  PIN issue_c_i[30]
    DIRECTION INPUT ;
    USE SIGNAL ;
    PORT
      LAYER Metal3 ;
        RECT  1149.6 937.66 1150 938.06 ;
    END
  END issue_c_i[30]
  PIN issue_c_i[31]
    DIRECTION INPUT ;
    USE SIGNAL ;
    PORT
      LAYER Metal3 ;
        RECT  1149.6 941.02 1150 941.42 ;
    END
  END issue_c_i[31]
  PIN issue_c_i[32]
    DIRECTION INPUT ;
    USE SIGNAL ;
    PORT
      LAYER Metal3 ;
        RECT  1149.6 944.38 1150 944.78 ;
    END
  END issue_c_i[32]
  PIN issue_c_i[33]
    DIRECTION INPUT ;
    USE SIGNAL ;
    PORT
      LAYER Metal3 ;
        RECT  1149.6 947.74 1150 948.14 ;
    END
  END issue_c_i[33]
  PIN issue_c_i[34]
    DIRECTION INPUT ;
    USE SIGNAL ;
    PORT
      LAYER Metal3 ;
        RECT  1149.6 951.1 1150 951.5 ;
    END
  END issue_c_i[34]
  PIN issue_c_i[35]
    DIRECTION INPUT ;
    USE SIGNAL ;
    PORT
      LAYER Metal3 ;
        RECT  1149.6 954.46 1150 954.86 ;
    END
  END issue_c_i[35]
  PIN issue_c_i[36]
    DIRECTION INPUT ;
    USE SIGNAL ;
    PORT
      LAYER Metal3 ;
        RECT  1149.6 957.82 1150 958.22 ;
    END
  END issue_c_i[36]
  PIN issue_c_i[37]
    DIRECTION INPUT ;
    USE SIGNAL ;
    PORT
      LAYER Metal3 ;
        RECT  1149.6 961.18 1150 961.58 ;
    END
  END issue_c_i[37]
  PIN issue_c_i[38]
    DIRECTION INPUT ;
    USE SIGNAL ;
    PORT
      LAYER Metal3 ;
        RECT  1149.6 964.54 1150 964.94 ;
    END
  END issue_c_i[38]
  PIN issue_c_i[39]
    DIRECTION INPUT ;
    USE SIGNAL ;
    PORT
      LAYER Metal3 ;
        RECT  1149.6 967.9 1150 968.3 ;
    END
  END issue_c_i[39]
  PIN issue_c_i[3]
    DIRECTION INPUT ;
    USE SIGNAL ;
    PORT
      LAYER Metal3 ;
        RECT  1149.6 846.94 1150 847.34 ;
    END
  END issue_c_i[3]
  PIN issue_c_i[40]
    DIRECTION INPUT ;
    USE SIGNAL ;
    PORT
      LAYER Metal3 ;
        RECT  1149.6 971.26 1150 971.66 ;
    END
  END issue_c_i[40]
  PIN issue_c_i[41]
    DIRECTION INPUT ;
    USE SIGNAL ;
    PORT
      LAYER Metal3 ;
        RECT  1149.6 974.62 1150 975.02 ;
    END
  END issue_c_i[41]
  PIN issue_c_i[42]
    DIRECTION INPUT ;
    USE SIGNAL ;
    PORT
      LAYER Metal3 ;
        RECT  1149.6 977.98 1150 978.38 ;
    END
  END issue_c_i[42]
  PIN issue_c_i[43]
    DIRECTION INPUT ;
    USE SIGNAL ;
    PORT
      LAYER Metal3 ;
        RECT  1149.6 981.34 1150 981.74 ;
    END
  END issue_c_i[43]
  PIN issue_c_i[44]
    DIRECTION INPUT ;
    USE SIGNAL ;
    PORT
      LAYER Metal3 ;
        RECT  1149.6 984.7 1150 985.1 ;
    END
  END issue_c_i[44]
  PIN issue_c_i[45]
    DIRECTION INPUT ;
    USE SIGNAL ;
    PORT
      LAYER Metal3 ;
        RECT  1149.6 988.06 1150 988.46 ;
    END
  END issue_c_i[45]
  PIN issue_c_i[46]
    DIRECTION INPUT ;
    USE SIGNAL ;
    PORT
      LAYER Metal3 ;
        RECT  1149.6 991.42 1150 991.82 ;
    END
  END issue_c_i[46]
  PIN issue_c_i[47]
    DIRECTION INPUT ;
    USE SIGNAL ;
    PORT
      LAYER Metal3 ;
        RECT  1149.6 994.78 1150 995.18 ;
    END
  END issue_c_i[47]
  PIN issue_c_i[48]
    DIRECTION INPUT ;
    USE SIGNAL ;
    PORT
      LAYER Metal3 ;
        RECT  1149.6 998.14 1150 998.54 ;
    END
  END issue_c_i[48]
  PIN issue_c_i[49]
    DIRECTION INPUT ;
    USE SIGNAL ;
    PORT
      LAYER Metal3 ;
        RECT  1149.6 1001.5 1150 1001.9 ;
    END
  END issue_c_i[49]
  PIN issue_c_i[4]
    DIRECTION INPUT ;
    USE SIGNAL ;
    PORT
      LAYER Metal3 ;
        RECT  1149.6 850.3 1150 850.7 ;
    END
  END issue_c_i[4]
  PIN issue_c_i[50]
    DIRECTION INPUT ;
    USE SIGNAL ;
    PORT
      LAYER Metal3 ;
        RECT  1149.6 1004.86 1150 1005.26 ;
    END
  END issue_c_i[50]
  PIN issue_c_i[51]
    DIRECTION INPUT ;
    USE SIGNAL ;
    PORT
      LAYER Metal3 ;
        RECT  1149.6 1008.22 1150 1008.62 ;
    END
  END issue_c_i[51]
  PIN issue_c_i[52]
    DIRECTION INPUT ;
    USE SIGNAL ;
    PORT
      LAYER Metal3 ;
        RECT  1149.6 1011.58 1150 1011.98 ;
    END
  END issue_c_i[52]
  PIN issue_c_i[53]
    DIRECTION INPUT ;
    USE SIGNAL ;
    PORT
      LAYER Metal3 ;
        RECT  1149.6 1014.94 1150 1015.34 ;
    END
  END issue_c_i[53]
  PIN issue_c_i[54]
    DIRECTION INPUT ;
    USE SIGNAL ;
    PORT
      LAYER Metal3 ;
        RECT  1149.6 1018.3 1150 1018.7 ;
    END
  END issue_c_i[54]
  PIN issue_c_i[55]
    DIRECTION INPUT ;
    USE SIGNAL ;
    PORT
      LAYER Metal3 ;
        RECT  1149.6 1021.66 1150 1022.06 ;
    END
  END issue_c_i[55]
  PIN issue_c_i[56]
    DIRECTION INPUT ;
    USE SIGNAL ;
    PORT
      LAYER Metal3 ;
        RECT  1149.6 1025.02 1150 1025.42 ;
    END
  END issue_c_i[56]
  PIN issue_c_i[57]
    DIRECTION INPUT ;
    USE SIGNAL ;
    PORT
      LAYER Metal3 ;
        RECT  1149.6 1028.38 1150 1028.78 ;
    END
  END issue_c_i[57]
  PIN issue_c_i[58]
    DIRECTION INPUT ;
    USE SIGNAL ;
    PORT
      LAYER Metal3 ;
        RECT  1149.6 1031.74 1150 1032.14 ;
    END
  END issue_c_i[58]
  PIN issue_c_i[59]
    DIRECTION INPUT ;
    USE SIGNAL ;
    PORT
      LAYER Metal3 ;
        RECT  1149.6 1035.1 1150 1035.5 ;
    END
  END issue_c_i[59]
  PIN issue_c_i[5]
    DIRECTION INPUT ;
    USE SIGNAL ;
    PORT
      LAYER Metal3 ;
        RECT  1149.6 853.66 1150 854.06 ;
    END
  END issue_c_i[5]
  PIN issue_c_i[60]
    DIRECTION INPUT ;
    USE SIGNAL ;
    PORT
      LAYER Metal3 ;
        RECT  1149.6 1038.46 1150 1038.86 ;
    END
  END issue_c_i[60]
  PIN issue_c_i[61]
    DIRECTION INPUT ;
    USE SIGNAL ;
    PORT
      LAYER Metal3 ;
        RECT  1149.6 1041.82 1150 1042.22 ;
    END
  END issue_c_i[61]
  PIN issue_c_i[62]
    DIRECTION INPUT ;
    USE SIGNAL ;
    PORT
      LAYER Metal3 ;
        RECT  1149.6 1045.18 1150 1045.58 ;
    END
  END issue_c_i[62]
  PIN issue_c_i[63]
    DIRECTION INPUT ;
    USE SIGNAL ;
    PORT
      LAYER Metal3 ;
        RECT  1149.6 1048.54 1150 1048.94 ;
    END
  END issue_c_i[63]
  PIN issue_c_i[6]
    DIRECTION INPUT ;
    USE SIGNAL ;
    PORT
      LAYER Metal3 ;
        RECT  1149.6 857.02 1150 857.42 ;
    END
  END issue_c_i[6]
  PIN issue_c_i[7]
    DIRECTION INPUT ;
    USE SIGNAL ;
    PORT
      LAYER Metal3 ;
        RECT  1149.6 860.38 1150 860.78 ;
    END
  END issue_c_i[7]
  PIN issue_c_i[8]
    DIRECTION INPUT ;
    USE SIGNAL ;
    PORT
      LAYER Metal3 ;
        RECT  1149.6 863.74 1150 864.14 ;
    END
  END issue_c_i[8]
  PIN issue_c_i[9]
    DIRECTION INPUT ;
    USE SIGNAL ;
    PORT
      LAYER Metal3 ;
        RECT  1149.6 867.1 1150 867.5 ;
    END
  END issue_c_i[9]
  PIN issue_class_i[0]
    DIRECTION INPUT ;
    USE SIGNAL ;
    PORT
      LAYER Metal3 ;
        RECT  1149.6 369.82 1150 370.22 ;
    END
  END issue_class_i[0]
  PIN issue_class_i[1]
    DIRECTION INPUT ;
    USE SIGNAL ;
    PORT
      LAYER Metal3 ;
        RECT  1149.6 373.18 1150 373.58 ;
    END
  END issue_class_i[1]
  PIN issue_class_i[2]
    DIRECTION INPUT ;
    USE SIGNAL ;
    PORT
      LAYER Metal3 ;
        RECT  1149.6 376.54 1150 376.94 ;
    END
  END issue_class_i[2]
  PIN issue_op_i[0]
    DIRECTION INPUT ;
    USE SIGNAL ;
    PORT
      LAYER Metal3 ;
        RECT  1149.6 379.9 1150 380.3 ;
    END
  END issue_op_i[0]
  PIN issue_op_i[1]
    DIRECTION INPUT ;
    USE SIGNAL ;
    PORT
      LAYER Metal3 ;
        RECT  1149.6 383.26 1150 383.66 ;
    END
  END issue_op_i[1]
  PIN issue_op_i[2]
    DIRECTION INPUT ;
    USE SIGNAL ;
    PORT
      LAYER Metal3 ;
        RECT  1149.6 386.62 1150 387.02 ;
    END
  END issue_op_i[2]
  PIN issue_op_i[3]
    DIRECTION INPUT ;
    USE SIGNAL ;
    PORT
      LAYER Metal3 ;
        RECT  1149.6 389.98 1150 390.38 ;
    END
  END issue_op_i[3]
  PIN issue_op_i[4]
    DIRECTION INPUT ;
    USE SIGNAL ;
    PORT
      LAYER Metal3 ;
        RECT  1149.6 393.34 1150 393.74 ;
    END
  END issue_op_i[4]
  PIN issue_op_i[5]
    DIRECTION INPUT ;
    USE SIGNAL ;
    PORT
      LAYER Metal3 ;
        RECT  1149.6 396.7 1150 397.1 ;
    END
  END issue_op_i[5]
  PIN issue_op_i[6]
    DIRECTION INPUT ;
    USE SIGNAL ;
    PORT
      LAYER Metal3 ;
        RECT  1149.6 400.06 1150 400.46 ;
    END
  END issue_op_i[6]
  PIN issue_op_i[7]
    DIRECTION INPUT ;
    USE SIGNAL ;
    PORT
      LAYER Metal3 ;
        RECT  1149.6 403.42 1150 403.82 ;
    END
  END issue_op_i[7]
  PIN issue_valid_i
    DIRECTION INPUT ;
    USE SIGNAL ;
    PORT
      LAYER Metal3 ;
        RECT  1149.6 366.46 1150 366.86 ;
    END
  END issue_valid_i
  PIN ready_o[0]
    DIRECTION OUTPUT ;
    USE SIGNAL ;
    PORT
      LAYER Metal3 ;
        RECT  1149.6 101.02 1150 101.42 ;
    END
  END ready_o[0]
  PIN ready_o[1]
    DIRECTION OUTPUT ;
    USE SIGNAL ;
    PORT
      LAYER Metal3 ;
        RECT  1149.6 104.38 1150 104.78 ;
    END
  END ready_o[1]
  PIN ready_o[2]
    DIRECTION OUTPUT ;
    USE SIGNAL ;
    PORT
      LAYER Metal3 ;
        RECT  1149.6 107.74 1150 108.14 ;
    END
  END ready_o[2]
  PIN reset_i
    DIRECTION INPUT ;
    USE SIGNAL ;
    PORT
      LAYER Metal2 ;
        RECT  287.32 1149.6 287.72 1150 ;
    END
  END reset_i
  PIN sync_valid_i
    DIRECTION INPUT ;
    USE SIGNAL ;
    PORT
      LAYER Metal3 ;
        RECT  1149.6 363.1 1150 363.5 ;
    END
  END sync_valid_i
  PIN VPWR
    DIRECTION INOUT ;
    USE POWER ;
    PORT
      LAYER TopMetal1 ;
        RECT  5.76 1124.12 1143.84 1126.12 ;
        RECT  5.76 1074.12 1143.84 1076.12 ;
        RECT  5.76 1024.12 1143.84 1026.12 ;
        RECT  5.76 974.12 1143.84 976.12 ;
        RECT  5.76 924.12 1143.84 926.12 ;
        RECT  5.76 874.12 1143.84 876.12 ;
        RECT  5.76 824.12 1143.84 826.12 ;
        RECT  5.76 774.12 1143.84 776.12 ;
        RECT  5.76 724.12 1143.84 726.12 ;
        RECT  5.76 674.12 1143.84 676.12 ;
        RECT  5.76 624.12 1143.84 626.12 ;
        RECT  5.76 574.12 1143.84 576.12 ;
        RECT  5.76 524.12 1143.84 526.12 ;
        RECT  5.76 474.12 1143.84 476.12 ;
        RECT  5.76 424.12 1143.84 426.12 ;
        RECT  5.76 374.12 1143.84 376.12 ;
        RECT  5.76 324.12 1143.84 326.12 ;
        RECT  5.76 274.12 1143.84 276.12 ;
        RECT  5.76 224.12 1143.84 226.12 ;
        RECT  5.76 174.12 1143.84 176.12 ;
        RECT  5.76 124.12 1143.84 126.12 ;
        RECT  5.76 74.12 1143.84 76.12 ;
        RECT  5.76 24.12 1143.84 26.12 ;
      LAYER Metal4 ;
        RECT  1115.26 14.9 1116.26 1134.22 ;
        RECT  1065.26 14.9 1066.26 1134.22 ;
        RECT  1015.26 14.9 1016.26 1134.22 ;
        RECT  965.26 14.9 966.26 1134.22 ;
        RECT  915.26 14.9 916.26 1134.22 ;
        RECT  865.26 14.9 866.26 1134.22 ;
        RECT  815.26 14.9 816.26 1134.22 ;
        RECT  765.26 14.9 766.26 1134.22 ;
        RECT  715.26 14.9 716.26 1134.22 ;
        RECT  665.26 14.9 666.26 1134.22 ;
        RECT  615.26 14.9 616.26 1134.22 ;
        RECT  565.26 14.9 566.26 1134.22 ;
        RECT  515.26 14.9 516.26 1134.22 ;
        RECT  465.26 14.9 466.26 1134.22 ;
        RECT  415.26 14.9 416.26 1134.22 ;
        RECT  365.26 14.9 366.26 1134.22 ;
        RECT  315.26 14.9 316.26 1134.22 ;
        RECT  265.26 14.9 266.26 1134.22 ;
        RECT  215.26 14.9 216.26 1134.22 ;
        RECT  165.26 14.9 166.26 1134.22 ;
        RECT  115.26 14.9 116.26 1134.22 ;
        RECT  65.26 14.9 66.26 1134.22 ;
        RECT  15.26 14.9 16.26 1134.22 ;
    END
  END VPWR
  PIN VGND
    DIRECTION INOUT ;
    USE GROUND ;
    PORT
      LAYER TopMetal1 ;
        RECT  5.76 1130.12 1143.84 1132.12 ;
        RECT  5.76 1080.12 1143.84 1082.12 ;
        RECT  5.76 1030.12 1143.84 1032.12 ;
        RECT  5.76 980.12 1143.84 982.12 ;
        RECT  5.76 930.12 1143.84 932.12 ;
        RECT  5.76 880.12 1143.84 882.12 ;
        RECT  5.76 830.12 1143.84 832.12 ;
        RECT  5.76 780.12 1143.84 782.12 ;
        RECT  5.76 730.12 1143.84 732.12 ;
        RECT  5.76 680.12 1143.84 682.12 ;
        RECT  5.76 630.12 1143.84 632.12 ;
        RECT  5.76 580.12 1143.84 582.12 ;
        RECT  5.76 530.12 1143.84 532.12 ;
        RECT  5.76 480.12 1143.84 482.12 ;
        RECT  5.76 430.12 1143.84 432.12 ;
        RECT  5.76 380.12 1143.84 382.12 ;
        RECT  5.76 330.12 1143.84 332.12 ;
        RECT  5.76 280.12 1143.84 282.12 ;
        RECT  5.76 230.12 1143.84 232.12 ;
        RECT  5.76 180.12 1143.84 182.12 ;
        RECT  5.76 130.12 1143.84 132.12 ;
        RECT  5.76 80.12 1143.84 82.12 ;
        RECT  5.76 30.12 1143.84 32.12 ;
      LAYER Metal4 ;
        RECT  1118.26 14.9 1119.26 1134.22 ;
        RECT  1068.26 14.9 1069.26 1134.22 ;
        RECT  1018.26 14.9 1019.26 1134.22 ;
        RECT  968.26 14.9 969.26 1134.22 ;
        RECT  918.26 14.9 919.26 1134.22 ;
        RECT  868.26 14.9 869.26 1134.22 ;
        RECT  818.26 14.9 819.26 1134.22 ;
        RECT  768.26 14.9 769.26 1134.22 ;
        RECT  718.26 14.9 719.26 1134.22 ;
        RECT  668.26 14.9 669.26 1134.22 ;
        RECT  618.26 14.9 619.26 1134.22 ;
        RECT  568.26 14.9 569.26 1134.22 ;
        RECT  518.26 14.9 519.26 1134.22 ;
        RECT  468.26 14.9 469.26 1134.22 ;
        RECT  418.26 14.9 419.26 1134.22 ;
        RECT  368.26 14.9 369.26 1134.22 ;
        RECT  318.26 14.9 319.26 1134.22 ;
        RECT  268.26 14.9 269.26 1134.22 ;
        RECT  218.26 14.9 219.26 1134.22 ;
        RECT  168.26 14.9 169.26 1134.22 ;
        RECT  118.26 14.9 119.26 1134.22 ;
        RECT  68.26 14.9 69.26 1134.22 ;
        RECT  18.26 14.9 19.26 1134.22 ;
    END
  END VGND
  OBS
    LAYER Metal1 ;
     RECT  2.735 0.82 1150 1150 ;
    LAYER Metal2 ;
     RECT  2.735 0.82 1150 1150 ;
    LAYER Metal3 ;
     RECT  2.735 0.82 1150 1150 ;
    LAYER Metal4 ;
     RECT  2.735 0.82 1150 1150 ;
    LAYER TopMetal1 ;
     RECT  2.735 0.82 1150 1150 ;
  END
END ino_exec_arith
END LIBRARY
